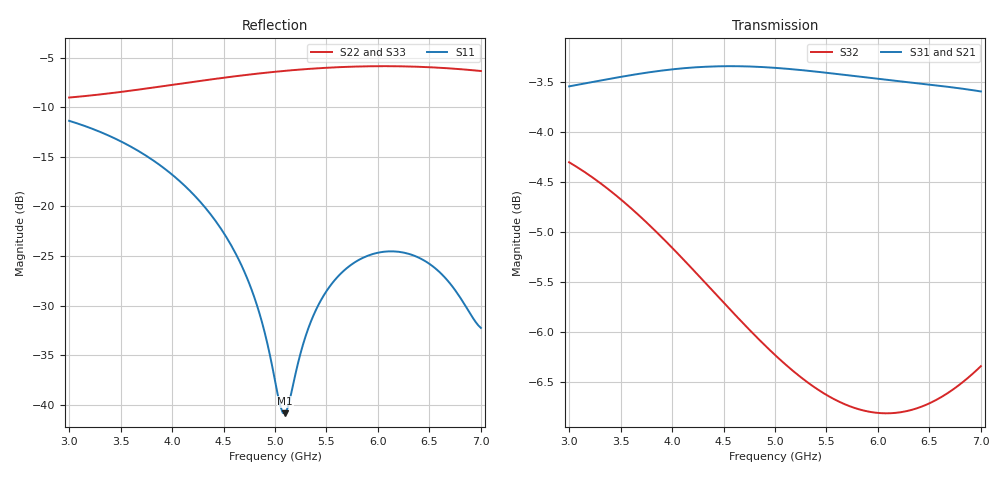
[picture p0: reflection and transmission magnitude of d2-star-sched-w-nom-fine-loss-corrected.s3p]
! yapnr Order 0 prediction d2-star-sched-w-nom-fine: predictions/D2/variants/d2-star-sched-w-nom/fine.s3p, loss-corrected
! substrate W-nom; coupon model OSHPARK-4L-FR408HR; correction: ratio (port line)
! |S21|, |S31| (and S12, S13) scaled, phases kept; 50 ohm, e^(+jwt)
# GHz S RI R 50
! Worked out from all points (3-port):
!   161 points, 3 GHz to 7 GHz, reference 50 ohm
!   strongest paths, dB at 3 GHz, 4 GHz, 5 GHz, 6 GHz, 7 GHz:
!     S31: -3.5, -3.4, -3.4, -3.5, -3.6
!     S21: -3.5, -3.4, -3.4, -3.5, -3.6
!     S32: -4.3, -5.2, -6.2, -6.8, -6.3
!   lowest |S11| = -40.9 dB at 5.1 GHz (marker M1), VSWR 1.02, Z = 49.5 + j0.743 ohm
!   |S11| at or under -10 dB: start of sweep to end of sweep
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3  -0.0916 0.2538  -0.3616 -0.5584  -0.3616 -0.5584
   -0.3615 -0.5579  0.3088 0.1719  -0.5772 -0.1949
   -0.3615 -0.5579  -0.5772 -0.1949  0.3088 0.1719
3.6  0.00437 0.1998  -0.5777 -0.3466  -0.5777 -0.3466
     -0.5774 -0.3467  0.3795 -0.0516  -0.561 0.1391
     -0.5774 -0.3467  -0.561 0.1391  0.3795 -0.0516
4.35  0.0439 0.0838  -0.6786 0.0331  -0.6786 0.0331
      -0.6793 0.0319  0.2803 -0.3315  -0.319 0.4214
      -0.6793 0.0319  -0.319 0.4214  0.2803 -0.3315
4.75  0.0243 0.0328  -0.6334 0.2443  -0.6334 0.2443
      -0.6352 0.2432  0.1562 -0.4343  -0.1517 0.4791
      -0.6352 0.2432  -0.1517 0.4791  0.1562 -0.4343
5  0.00376 0.0127  -0.5708 0.3646  -0.5708 0.3646
   -0.5733 0.3641  0.063 -0.4725  -0.0495 0.4856
   -0.5733 0.3641  -0.0495 0.4856  0.063 -0.4725
5.1  -0.00507 0.00751  -0.5391 0.4087  -0.5391 0.4087
     -0.5418 0.4085  0.0238 -0.4815  -0.0103 0.4828
     -0.5418 0.4085  -0.0103 0.4828  0.0238 -0.4815
5.425  -0.0321 0.00124  -0.4135 0.5313  -0.4135 0.5313
       -0.4165 0.5324  -0.106 -0.4852  0.1083 0.4561
       -0.4165 0.5324  0.1083 0.4561  -0.106 -0.4852
5.875  -0.0545 0.0114  -0.1973 0.6387  -0.1973 0.6387
       -0.1993 0.6415  -0.2733 -0.4278  0.2482 0.3846
       -0.1993 0.6415  0.2482 0.3846  -0.2733 -0.4278
6.475  -0.0464 0.0243  0.1233 0.6513  0.1233 0.6513
       0.1245 0.6546  -0.43 -0.2614  0.3924 0.2422
       0.1245 0.6546  0.3924 0.2422  -0.43 -0.2614
7  -0.0244 -0.000873  0.3839 0.5347  0.3839 0.5347
   0.3873 0.5355  -0.4751 -0.075  0.4762 0.0739
   0.3873 0.5355  0.4762 0.0739  -0.4751 -0.075
